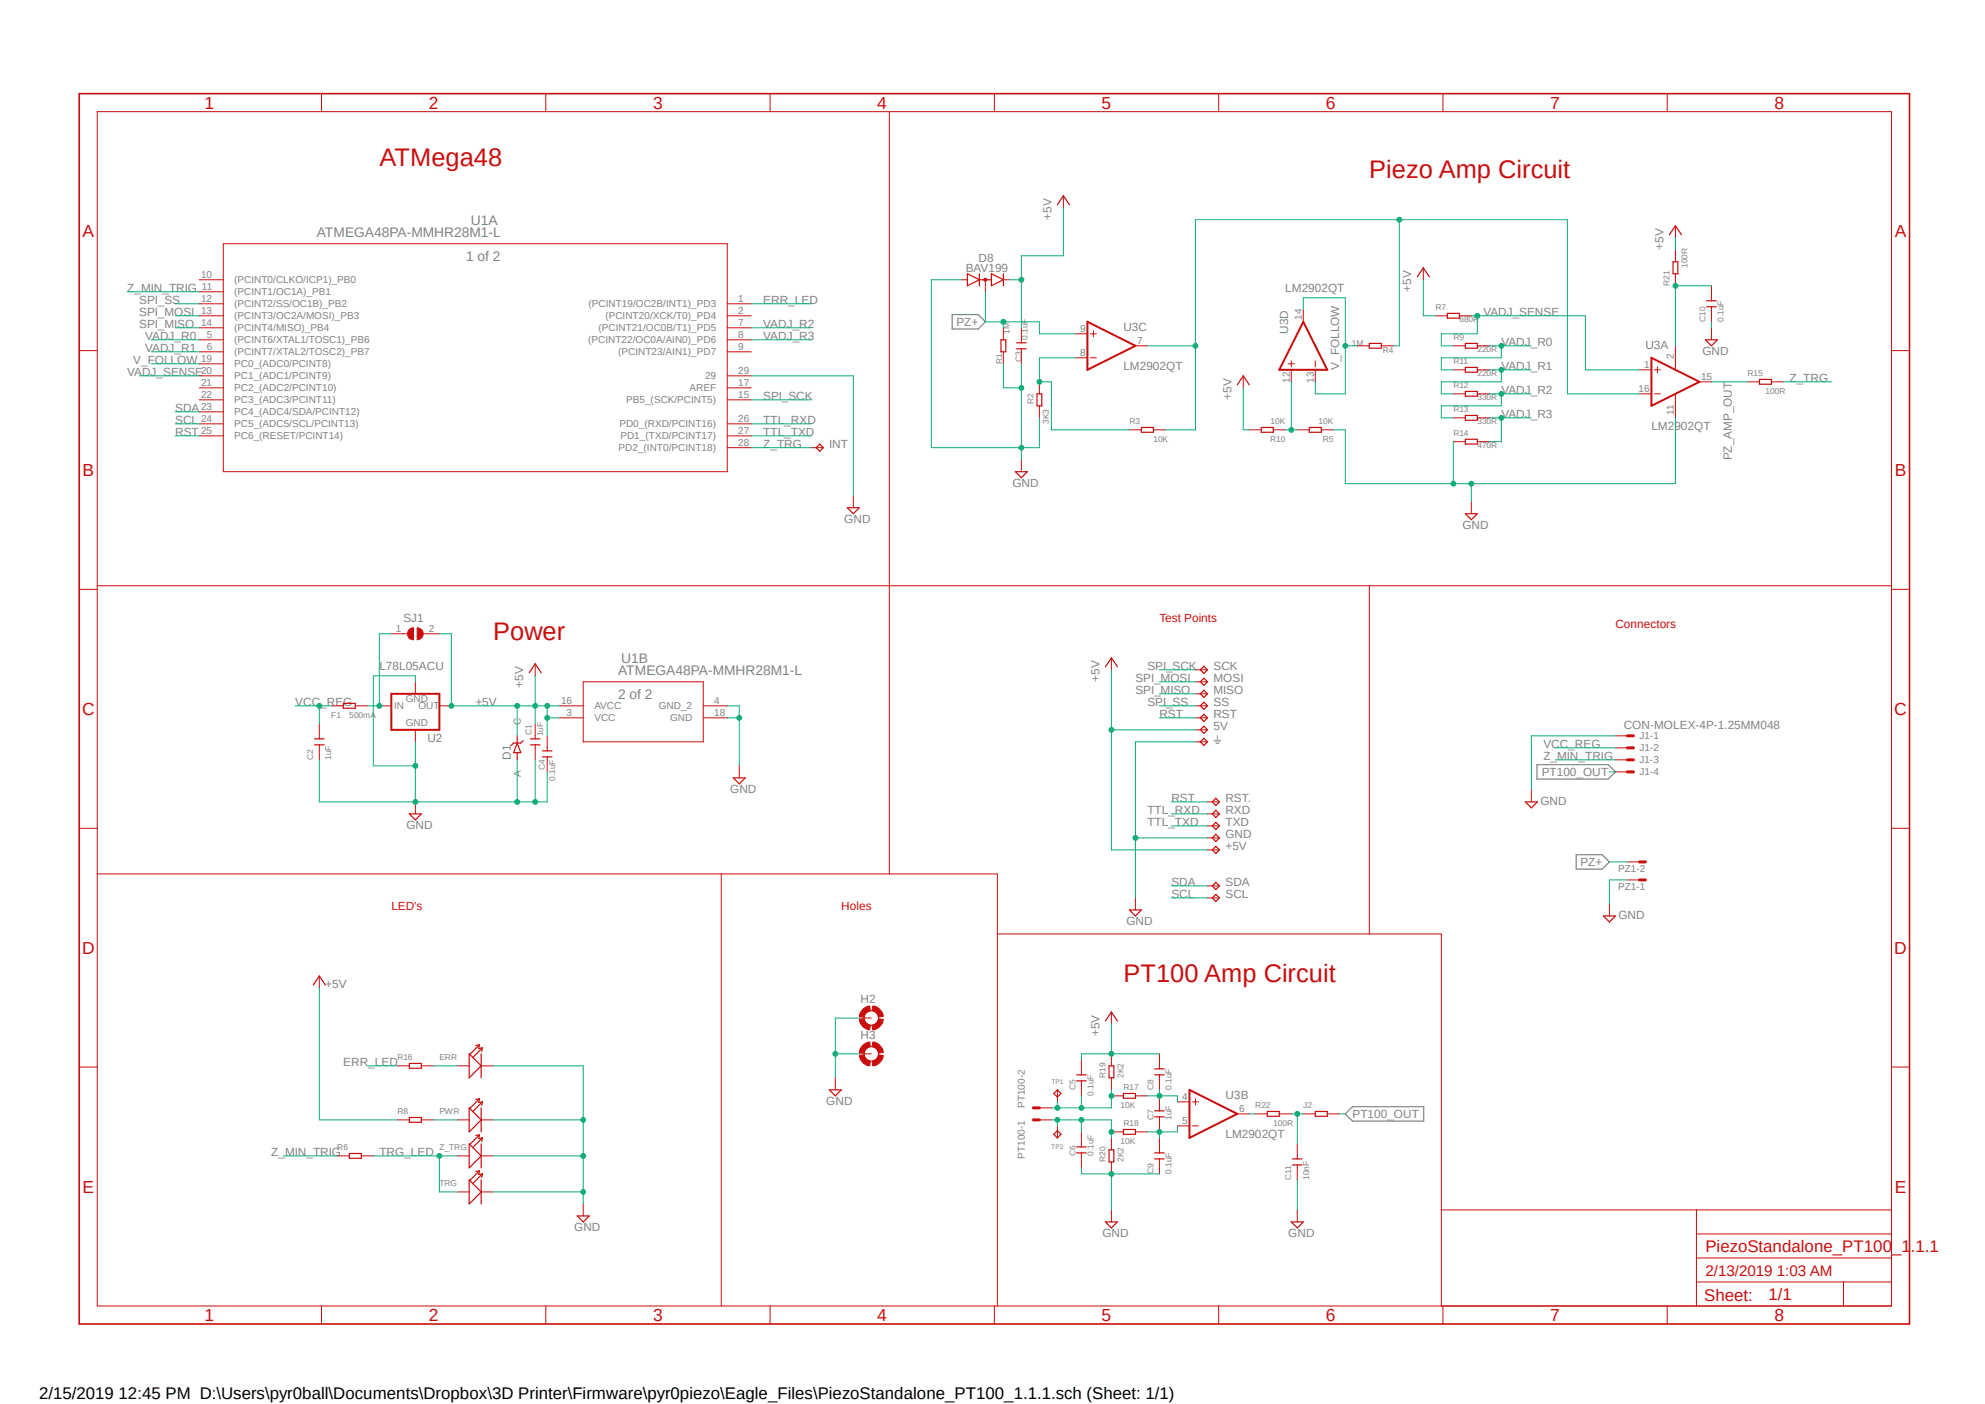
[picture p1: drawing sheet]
<svg xmlns="http://www.w3.org/2000/svg" width="420mm" height="297mm" viewBox="0 0 420 297" stroke-linecap="round" stroke-linejoin="round" font-family="sans-serif">
<defs><g id="words">
<g font-size="5.4" fill="#c90d0c">
<text x="80.3" y="35.1">ATMega48</text>
<text x="289.7" y="37.6">Piezo Amp Circuit</text>
<text x="104.3" y="135.3">Power</text>
<text x="237.7" y="207.7">PT100 Amp Circuit</text>
</g>
<g font-size="3.7" fill="#c90d0c">
<text x="43.3" y="23">1</text>
<text x="90.7" y="23">2</text>
<text x="138.2" y="23">3</text>
<text x="185.6" y="23">4</text>
<text x="233.1" y="23">5</text>
<text x="280.5" y="23">6</text>
<text x="328" y="23">7</text>
<text x="375.5" y="23">8</text>
<text x="17.4" y="50.2">A</text>
<text x="400.9" y="50.2">A</text>
<text x="17.4" y="100.7">B</text>
<text x="400.9" y="100.7">B</text>
<text x="17.4" y="151.3">C</text>
<text x="400.8" y="151.3">C</text>
<text x="17.4" y="201.8">D</text>
<text x="400.8" y="201.8">D</text>
<text x="17.4" y="252.3">E</text>
<text x="400.9" y="252.3">E</text>
<text x="43.3" y="279.5">1</text>
<text x="90.7" y="279.5">2</text>
<text x="138.2" y="279.5">3</text>
<text x="185.6" y="279.5">4</text>
<text x="233.1" y="279.5">5</text>
<text x="280.5" y="279.5">6</text>
<text x="328" y="279.5">7</text>
<text x="375.5" y="279.5">8</text>
</g>
<g font-size="3.6" fill="#c90d0c">
<text x="360.8" y="264.8">PiezoStandalone_PT100_1.1.1</text>
<text x="360.6" y="275.1">Sheet:</text>
<text x="374.2" y="275">1/1</text>
</g>
<text font-size="3.6" x="8.3" y="295.9">2/15/2019 12:45 PM D:\Users\pyr0ball\Documents\Dropbox\3D Printer\Firmware\pyr0piezo\Eagle_Files\PiezoStandalone_PT100_1.1.1.sch (Sheet: 1/1)</text>
<text font-size="3.2" fill="#c90d0c" x="360.8" y="269.9">2/13/2019 1:03 AM</text>
<g font-size="2.9" fill="#808080">
<text x="99.6" y="47.5">U1A</text>
<text x="67" y="50">ATMEGA48PA-MMHR28M1-L</text>
<text x="98.6" y="55.1">1 of 2</text>
<text x="130.8" y="142.7">ATMEGA48PA-MMHR28M1-L</text>
<text x="131.4" y="140.2">U1B</text>
<text x="130.8" y="147.8">2 of 2</text>
</g>
<g font-size="2.5" fill="#808080">
<text x="222.5" y="46.5" transform="rotate(-90 222.5 46.5)">+5V</text>
<text x="352" y="52.8" transform="rotate(-90 352 52.8)">+5V</text>
<text x="204.3" y="57.5">BAV199</text>
<text x="207.1" y="55.3">D8</text>
<text x="26.9" y="61.7">Z_MIN_TRIG</text>
<text x="29.5" y="64.3">SPI_SS</text>
<text x="161.5" y="64.3">ERR_LED</text>
<text x="271.9" y="61.7">LM2902QT</text>
<text x="298.6" y="61.7" transform="rotate(-90 298.6 61.7)">+5V</text>
<text x="29.5" y="69.3">SPI_MISO</text>
<text x="29.5" y="66.8">SPI_MOSI</text>
<text x="30.7" y="71.9">VADJ_R0</text>
<text x="161.5" y="69.3">VADJ_R2</text>
<text x="161.5" y="71.9">VADJ_R3</text>
<text x="202.4" y="69">PZ+</text>
<text x="237.7" y="70">U3C</text>
<text x="272.6" y="70.6" transform="rotate(-90 272.6 70.6)">U3D</text>
<text x="313.9" y="66.8">VADJ_SENSE</text>
<text x="28.2" y="77">V_FOLLOW</text>
<text x="30.7" y="74.4">VADJ_R1</text>
<text x="317.7" y="73.2">VADJ_R0</text>
<text x="348.1" y="73.8">U3A</text>
<text x="360.2" y="75.1">GND</text>
<text x="26.9" y="79.5">VADJ_SENSE</text>
<text x="237.7" y="78.2">LM2902QT</text>
<text x="283.4" y="78.2" transform="rotate(-90 283.4 78.2)">V_FOLLOW</text>
<text x="317.7" y="78.2">VADJ_R1</text>
<text x="317.7" y="83.3">VADJ_R2</text>
<text x="378.6" y="80.8">Z_TRG</text>
<text x="37.1" y="87.1">SDA</text>
<text x="37.1" y="89.7">SCL</text>
<text x="161.5" y="89.7">TTL_RXD</text>
<text x="161.5" y="84.6">SPI_SCK</text>
<text x="260.6" y="84.6" transform="rotate(-90 260.6 84.6)">+5V</text>
<text x="317.7" y="88.4">VADJ_R3</text>
<text x="37.1" y="92.2">RST</text>
<text x="161.5" y="92.2">TTL_TXD</text>
<text x="161.5" y="94.7">Z_TRG</text>
<text x="175.5" y="94.7">INT</text>
<text x="349.4" y="90.9">LM2902QT</text>
<text x="366.4" y="97.4" transform="rotate(-90 366.4 97.4)">PZ_AMP_OUT</text>
<text x="214.2" y="103">GND</text>
<text x="178.6" y="110.6">GND</text>
<text x="309.4" y="111.8">GND</text>
<text x="85.3" y="131.5">SJ1</text>
<text x="80.3" y="141.7">L78L05ACU</text>
<text x="242.8" y="141.7">SPI_SCK</text>
<text x="256.8" y="141.7">SCK</text>
<text x="62.5" y="149.3">VCC_REG</text>
<text x="100.6" y="149.3">+5V</text>
<text x="110.7" y="145.5" transform="rotate(-90 110.7 145.5)">+5V</text>
<text x="232.6" y="144.2" transform="rotate(-90 232.6 144.2)">+5V</text>
<text x="240.2" y="146.8">SPI_MISO</text>
<text x="240.2" y="144.2">SPI_MOSI</text>
<text x="242.8" y="149.3">SPI_SS</text>
<text x="256.8" y="144.2">MOSI</text>
<text x="256.8" y="146.8">MISO</text>
<text x="256.8" y="149.3">SS</text>
<text x="245.3" y="151.9">RST</text>
<text x="256.8" y="151.9">RST</text>
<text x="256.8" y="154.4">5V</text>
<text x="343.6" y="154.3">CON-MOLEX-4P-1.25MM048</text>
<text x="90.4" y="156.9">U2</text>
<text x="108.1" y="160.7" transform="rotate(-90 108.1 160.7)">D1</text>
<text x="256.8" y="157.4">⏚</text>
<text x="326.6" y="160.7">Z_MIN_TRIG</text>
<text x="326.6" y="158.2">VCC_REG</text>
<text x="154.5" y="167.7">GND</text>
<text x="326.2" y="164.2">PT100_OUT</text>
<text x="242.8" y="172.2">TTL_RXD</text>
<text x="247.9" y="169.6">RST</text>
<text x="259.3" y="172.2">RXD</text>
<text x="259.3" y="169.6">RST.</text>
<text x="325.9" y="170.3">GND</text>
<text x="86" y="175.3">GND</text>
<text x="242.8" y="174.7">TTL_TXD</text>
<text x="259.3" y="174.7">TXD</text>
<text x="259.3" y="177.2">GND</text>
<text x="259.3" y="179.8">+5V</text>
<text x="334.4" y="183.2">PZ+</text>
<text x="247.9" y="187.4">SDA</text>
<text x="247.9" y="190">SCL</text>
<text x="259.3" y="187.4">SDA</text>
<text x="259.3" y="190">SCL</text>
<text x="238.3" y="195.7">GND</text>
<text x="342.4" y="194.4">GND</text>
<text x="68.8" y="209">+5V</text>
<text x="182.1" y="212.2">H2</text>
<text x="182.1" y="219.8">H3</text>
<text x="232.6" y="219.2" transform="rotate(-90 232.6 219.2)">+5V</text>
<text x="72.6" y="225.5">ERR_LED</text>
<text x="174.8" y="233.7">GND</text>
<text x="259.3" y="232.5">U3B</text>
<text x="286.2" y="236.5">PT100_OUT</text>
<text x="57.4" y="244.5">Z_MIN_TRIG</text>
<text x="80.3" y="244.5">TRG_LED</text>
<text x="259.3" y="240.7">LM2902QT</text>
<text x="121.5" y="260.4">GND</text>
<text x="233.3" y="261.7">GND</text>
<text x="272.6" y="261.7">GND</text>
</g>
<g font-size="2.5" fill="#c90d0c">
<text x="245.3" y="131.5">Test Points</text>
<text x="341.8" y="132.8">Connectors</text>
<text x="82.8" y="192.5">LED's</text>
<text x="178" y="192.5">Holes</text>
</g>
<g font-size="2.1" fill="#808080">
<text x="42.5" y="58.8">10</text>
<text x="49.6" y="59.9">(PCINT0/CLKO/ICP1)_PB0</text>
<text x="42.5" y="63.9">12</text>
<text x="42.7" y="61.3">11</text>
<text x="49.6" y="62.5">(PCINT1/OC1A)_PB1</text>
<text x="49.6" y="65">(PCINT2/SS/OC1B)_PB2</text>
<text x="124.5" y="65">(PCINT19/OC2B/INT1)_PD3</text>
<text x="156.2" y="63.9">1</text>
<text x="42.5" y="66.4">13</text>
<text x="42.5" y="69">14</text>
<text x="43.7" y="71.5">5</text>
<text x="49.6" y="67.6">(PCINT3/OC2A/MOSI)_PB3</text>
<text x="49.6" y="70.1">(PCINT4/MISO)_PB4</text>
<text x="126.7" y="70.1">(PCINT21/OC0B/T1)_PD5</text>
<text x="128.1" y="67.6">(PCINT20/XCK/T0)_PD4</text>
<text x="156.2" y="66.4">2</text>
<text x="156.2" y="69">7</text>
<text x="156.2" y="71.5">8</text>
<text x="228.5" y="70.2">9</text>
<text x="275.4" y="67.7" transform="rotate(-90 275.4 67.7)">14</text>
<text x="42.5" y="76.6">19</text>
<text x="43.7" y="74">6</text>
<text x="49.6" y="72.6">(PCINT6/XTAL1/TOSC1)_PB6</text>
<text x="49.6" y="75.2">(PCINT7/XTAL2/TOSC2)_PB7</text>
<text x="49.6" y="77.7">PC0_(ADC0/PCINT8)</text>
<text x="124.5" y="72.6">(PCINT22/OC0A/AIN0)_PD6</text>
<text x="130.8" y="75.2">(PCINT23/AIN1)_PD7</text>
<text x="156.2" y="74">9</text>
<text x="228.5" y="75.3">8</text>
<text x="240.6" y="72.8">7</text>
<text x="347.9" y="77.9">1</text>
<text x="354.2" y="75.9" transform="rotate(-90 354.2 75.9)">2</text>
<text x="42.5" y="79.1">20</text>
<text x="42.5" y="81.7">21</text>
<text x="49.6" y="80.3">PC1_(ADC1/PCINT9)</text>
<text x="49.6" y="82.8">PC2_(ADC2/PCINT10)</text>
<text x="145.9" y="82.8">AREF</text>
<text x="149.2" y="80.3">29</text>
<text x="156.2" y="79.1">29</text>
<text x="156.2" y="81.7">17</text>
<text x="272.9" y="80.9" transform="rotate(-90 272.9 80.9)">12</text>
<text x="278" y="80.9" transform="rotate(-90 278 80.9)">13</text>
<text x="346.7" y="82.9">16</text>
<text x="359.9" y="80.4">15</text>
<text x="42.5" y="84.2">22</text>
<text x="42.5" y="86.7">23</text>
<text x="42.5" y="89.3">24</text>
<text x="49.6" y="85.3">PC3_(ADC3/PCINT11)</text>
<text x="49.6" y="87.9">PC4_(ADC4/SDA/PCINT12)</text>
<text x="132.5" y="85.3">PB5_(SCK/PCINT5)</text>
<text x="156.2" y="84.2">15</text>
<text x="156.2" y="89.3">26</text>
<text x="354.2" y="87.8" transform="rotate(-90 354.2 87.8)">11</text>
<text x="42.5" y="91.8">25</text>
<text x="49.6" y="90.4">PC5_(ADC5/SCL/PCINT13)</text>
<text x="49.6" y="93">PC6_(RESET/PCINT14)</text>
<text x="130.9" y="95.5">PD2_(INT0/PCINT18)</text>
<text x="131.1" y="90.4">PD0_(RXD/PCINT16)</text>
<text x="131.3" y="93">PD1_(TXD/PCINT17)</text>
<text x="156.2" y="91.8">27</text>
<text x="156.2" y="94.4">28</text>
<text x="83.8" y="133.7">1</text>
<text x="90.8" y="133.7">2</text>
<text x="83.4" y="149.9">IN</text>
<text x="85.9" y="148.5">GND</text>
<text x="88.5" y="149.9">OUT</text>
<text x="118.7" y="149">16</text>
<text x="151.1" y="149">4</text>
<text x="85.9" y="153.6">GND</text>
<text x="110.2" y="153.3" transform="rotate(-90 110.2 153.3)">C</text>
<text x="119.9" y="151.5">3</text>
<text x="125.8" y="150.1">AVCC</text>
<text x="125.8" y="152.6">VCC</text>
<text x="139.4" y="150.1">GND_2</text>
<text x="141.8" y="152.6">GND</text>
<text x="151.1" y="151.5">18</text>
<text x="346.9" y="156.4">J1-1</text>
<text x="346.9" y="159">J1-2</text>
<text x="346.9" y="161.5">J1-3</text>
<text x="110.2" y="164.5" transform="rotate(-90 110.2 164.5)">A</text>
<text x="346.9" y="164">J1-4</text>
<text x="342.3" y="184.4">PZ1-2</text>
<text x="342.3" y="188.2">PZ1-1</text>
<text x="250.1" y="232.7">4</text>
<text x="216.9" y="234.4" transform="rotate(-90 216.9 234.4)">PT100-2</text>
<text x="250.1" y="237.8">5</text>
<text x="262.2" y="235.3">6</text>
<text x="216.9" y="245.1" transform="rotate(-90 216.9 245.1)">PT100-1</text>
</g>
<g font-size="1.8" fill="#808080">
<text x="357" y="56.6" transform="rotate(-90 357 56.6)">100R</text>
<text x="303.7" y="65.5">R7</text>
<text x="353.2" y="60.5" transform="rotate(-90 353.2 60.5)">R21</text>
<text x="213.6" y="70.6" transform="rotate(-90 213.6 70.6)">1M</text>
<text x="217.4" y="71.9" transform="rotate(-90 217.4 71.9)">0.1uF</text>
<text x="307.5" y="71.9">R9</text>
<text x="308.8" y="68.1">680R</text>
<text x="360.8" y="68.1" transform="rotate(-90 360.8 68.1)">C10</text>
<text x="364.7" y="68.1" transform="rotate(-90 364.7 68.1)">0.1uF</text>
<text x="212" y="77" transform="rotate(-90 212 77)">R1</text>
<text x="216.1" y="76.7" transform="rotate(-90 216.1 76.7)">C3</text>
<text x="286" y="73.2">1M</text>
<text x="292.6" y="74.7">R4</text>
<text x="307.5" y="77">R11</text>
<text x="312.6" y="74.4">220R</text>
<text x="307.5" y="82">R12</text>
<text x="312.6" y="79.5">220R</text>
<text x="369.7" y="79.5">R15</text>
<text x="373.5" y="83.3">100R</text>
<text x="218.7" y="85.6" transform="rotate(-90 218.7 85.6)">R2</text>
<text x="222" y="89.7" transform="rotate(-90 222 89.7)">3K3</text>
<text x="239" y="89.7">R3</text>
<text x="268.8" y="89.7">10K</text>
<text x="279" y="89.7">10K</text>
<text x="307.5" y="87.1">R13</text>
<text x="312.6" y="84.6">330R</text>
<text x="312.6" y="89.7">330R</text>
<text x="244.1" y="93.5">10K</text>
<text x="268.7" y="93.5">R10</text>
<text x="279.9" y="93.5">R5</text>
<text x="307.5" y="92.2">R14</text>
<text x="312.6" y="94.7">470R</text>
<text x="70.1" y="151.8">F1</text>
<text x="73.9" y="151.8">500mA</text>
<text x="112.5" y="155.5" transform="rotate(-90 112.5 155.5)">C1</text>
<text x="114.9" y="155.8" transform="rotate(-90 114.9 155.8)">1uF</text>
<text x="66.3" y="160.7" transform="rotate(-90 66.3 160.7)">C2</text>
<text x="70.1" y="160.7" transform="rotate(-90 70.1 160.7)">1uF</text>
<text x="115.3" y="162.9" transform="rotate(-90 115.3 162.9)">C4</text>
<text x="117.4" y="165.2" transform="rotate(-90 117.4 165.2)">0.1uF</text>
<text x="84.1" y="224.2">R16</text>
<text x="93" y="224.2">ERR</text>
<text x="227.5" y="230.5" transform="rotate(-90 227.5 230.5)">C5</text>
<text x="231.4" y="231.8" transform="rotate(-90 231.4 231.8)">0.1uF</text>
<text x="233.9" y="228" transform="rotate(-90 233.9 228)">R19</text>
<text x="237.7" y="228" transform="rotate(-90 237.7 228)">2K2</text>
<text x="237.7" y="230.5">R17</text>
<text x="244.1" y="230.5" transform="rotate(-90 244.1 230.5)">C8</text>
<text x="247.9" y="230.5" transform="rotate(-90 247.9 230.5)">0.1uF</text>
<text x="84.1" y="235.6">R8</text>
<text x="93" y="235.6">PWR</text>
<text x="237.1" y="234.4">10K</text>
<text x="237.7" y="238.2">R18</text>
<text x="244.1" y="236.9" transform="rotate(-90 244.1 236.9)">C7</text>
<text x="247.9" y="236.9" transform="rotate(-90 247.9 236.9)">1uF</text>
<text x="265.6" y="234.4">R22</text>
<text x="269.4" y="238.2">100R</text>
<text x="275.8" y="234.4">J2</text>
<text x="71.4" y="243.2">R6</text>
<text x="93" y="243.2">Z_TRG</text>
<text x="227.5" y="244.5" transform="rotate(-90 227.5 244.5)">C6</text>
<text x="231.4" y="244.5" transform="rotate(-90 231.4 244.5)">0.1uF</text>
<text x="233.9" y="245.8" transform="rotate(-90 233.9 245.8)">R20</text>
<text x="237.1" y="242">10K</text>
<text x="237.7" y="245.8" transform="rotate(-90 237.7 245.8)">2K2</text>
<text x="93" y="250.9">TRG</text>
<text x="244.1" y="248.3" transform="rotate(-90 244.1 248.3)">C9</text>
<text x="247.9" y="248.3" transform="rotate(-90 247.9 248.3)">0.1uF</text>
<text x="273.2" y="249.6" transform="rotate(-90 273.2 249.6)">C11</text>
<text x="277" y="249.6" transform="rotate(-90 277 249.6)">10nF</text>
</g>
<g font-size="1.4" fill="#808080">
<text x="222.5" y="229.3">TP1</text>
<text x="222.4" y="243">TP2</text>
</g>
</g></defs>
<path d="M16.3 19.5l395.7 261.1M412 19.5l-395.7 261.1" fill="none" stroke="#fff" stroke-width=".21"/>
<path d="M201.5 66.5h5.5l1.5 1.6-1.5 1.5h-5.5zM325.2 161.8h15.1l1.5 1.5-1.5 1.5h-15.1zM333.5 180.8h5.5l1.5 1.5-1.5 1.6h-5.5zM284.6 235.6l1.6-1.5h15v3.1h-15z" fill="none" stroke="#808080" stroke-width=".25"/>
<g fill="none" stroke="#c90d0c" stroke-width=".21">
<path d="M188.2 23.6v161.3M42.2 59.2h5M47.2 51.6h106.7v48.2h-106.7zM42.2 64.3h5M42.2 66.8h5M42.2 69.3h5M42.2 71.9h5M42.2 74.4h5M42.2 79.5h5M42.2 61.7h5M42.2 77h5M153.9 64.3h5.1"/>
<path d="M153.9 66.8h5.1M153.9 69.3h5.1M153.9 71.9h5.1M153.9 74.4h5.1M153.9 79.5h5.1M42.2 82h5M42.2 84.6h5M42.2 89.7h5M42.2 92.2h5M42.2 87.1h5M153.9 82h5.1M153.9 84.6h5.1"/>
<path d="M153.9 89.7h5.1M153.9 92.2h5.1M153.9 94.7h5.1M20.6 123.9h379.6M289.7 123.9v73.7M80.3 149.3h2.5M87.9 144.2v2.6M87.9 154.4v2.5M93 149.3h2.5M118.3 149.3h5.1M118.3 151.8h5.1M123.4 144.2h25.4v12.7h-25.4z"/>
<path d="M148.8 149.3h5.1M148.8 151.8h5.1M87.9 169.6v2.6M156.4 162v2.5M20.6 184.9h190.4v91.4M152.6 184.9v91.4M211 197.6h94v58.3M344.3 186.1h2.6M344.3 182.3h2.6M96.8 244.5h2.5M101.8 244.5h2.6"/>
<circle cx="184.4" cy="215.3" r="1.53"/>
</g>
<path d="M346.9 186.1h1.2M346.9 182.3h1.2" fill="none" stroke="#c90d0c" stroke-width=".63"/>
<path d="M82.8 146.8h10.2v7.6h-10.2z" fill="none" stroke="#c90d0c" stroke-width=".42"/>
<path d="M86.6 172.2h2.6l-1.3 1.2zM155.2 164.5h2.5l-1.3 1.3zM99.3 242l2.5 2.5-2.5 2.6zM101.4 240.1l-2 2M101.4 240.1l-.7 .1M101.4 240.1l-.1 .7 .8-.1M101.8 242v5.1M102.1 240.7l-2.1 2M102.1 240.7l-.2 .8" fill="none" stroke="#c90d0c" stroke-width=".25"/>
<path d="M184.7 212.8a2.44 2.44 0 0 1 2.2 2.2l-1 .1a1.56 1.56 0 0 0-1.4-1.3z" fill-rule="evenodd" fill="#c90d0c"/>
<path d="M184.7 212.8a2.44 2.44 0 0 1 2.2 2.2l-1 .1a1.56 1.56 0 0 0-1.4-1.3z" fill="none" stroke="#c90d0c" stroke-width=".21"/>
<path d="M182.8 213.3l1.2-.5 .1 1a1.57 1.57 0 0 0-1.3 1.3l-1-.1a2.35 2.35 0 0 1 1-1.7z" fill-rule="evenodd" fill="#c90d0c"/>
<path d="M182.8 213.3l1.2-.5 .1 1a1.57 1.57 0 0 0-1.3 1.3l-1-.1a2.35 2.35 0 0 1 1-1.7z" fill="none" stroke="#c90d0c" stroke-width=".21"/>
<path d="M181.8 215.6l1-.1a1.57 1.57 0 0 0 1.3 1.4l-.1 .9a2.45 2.45 0 0 1-2.2-2.2z" fill-rule="evenodd" fill="#c90d0c"/>
<path d="M181.8 215.6l1-.1a1.57 1.57 0 0 0 1.3 1.4l-.1 .9a2.45 2.45 0 0 1-2.2-2.2z" fill="none" stroke="#c90d0c" stroke-width=".21"/>
<path d="M185.9 215.5l1 .1a2.57 2.57 0 0 1-2.2 2.2l-.2-.9a1.56 1.56 0 0 0 1.4-1.4z" fill-rule="evenodd" fill="#c90d0c"/>
<g fill="none" stroke="#c90d0c" stroke-width=".21">
<path d="M181.8 215.3h2.6M184.5 216.9a1.56 1.56 0 0 0 1.4-1.4l1 .1a2.57 2.57 0 0 1-2.2 2.2z"/>
<circle cx="184.4" cy="222.9" r="1.53"/>
</g>
<path d="M184.7 220.4a2.44 2.44 0 0 1 2.2 2.2l-1 .2a1.56 1.56 0 0 0-1.4-1.4z" fill-rule="evenodd" fill="#c90d0c"/>
<path d="M184.7 220.4a2.44 2.44 0 0 1 2.2 2.2l-1 .2a1.56 1.56 0 0 0-1.4-1.4z" fill="none" stroke="#c90d0c" stroke-width=".21"/>
<path d="M182.8 220.9l1.2-.5 .1 1a1.57 1.57 0 0 0-1.3 1.4l-1-.2a2.35 2.35 0 0 1 1-1.7z" fill-rule="evenodd" fill="#c90d0c"/>
<path d="M182.8 220.9l1.2-.5 .1 1a1.57 1.57 0 0 0-1.3 1.4l-1-.2a2.35 2.35 0 0 1 1-1.7z" fill="none" stroke="#c90d0c" stroke-width=".21"/>
<path d="M181.8 223.3l1-.2a1.57 1.57 0 0 0 1.3 1.4l-.1 1a2.45 2.45 0 0 1-2.2-2.2z" fill-rule="evenodd" fill="#c90d0c"/>
<path d="M181.8 223.3l1-.2a1.57 1.57 0 0 0 1.3 1.4l-.1 1a2.45 2.45 0 0 1-2.2-2.2z" fill="none" stroke="#c90d0c" stroke-width=".21"/>
<path d="M185.9 223.1l1 .2a2.57 2.57 0 0 1-2.2 2.2l-.2-1a1.56 1.56 0 0 0 1.4-1.4z" fill-rule="evenodd" fill="#c90d0c"/>
<g fill="none" stroke="#c90d0c" stroke-width=".21">
<path d="M68 19.8v3.8M115.5 19.8v3.8M162.9 19.8v3.8M210.4 19.8v3.8M257.9 19.8v3.8M305.3 19.8v3.8M352.8 19.8v3.8M20.6 23.6h379.6v252.7h-379.6zM203.4 59.2h1.3M212.3 59.2h1.3M16.8 74.2h3.8M212.3 69.3v2.6"/>
<path d="M212.3 74.4v2.6M400.2 74.2h3.8M171.7 94.7h2.5M219.9 80.8v2.5M219.9 85.9v2.5M264.3 90.9h2.6M269.4 90.9h2.5M274.5 90.9h2.5M279.6 90.9h2.5M180.6 104.9v2.5M311.3 106.1v2.6M16.8 124.7h3.8"/>
<path d="M400.2 124.7h3.8M67.6 153.1v3.2M67.6 157.6v3.1M113.2 153.1v3.2M113.2 157.6v3.1M252.9 141.7h2.6M252.9 144.2h2.6M252.9 146.8h2.6M252.9 149.3h2.6M252.9 151.8h2.6M252.9 154.4h2.6M16.8 175.2h3.8"/>
<path d="M255.5 172.2h2.5M255.5 174.7h2.5M255.5 177.2h2.5M255.5 179.8h2.5M255.5 169.6h2.5M400.2 175.2h3.8M240.2 189.9v2.6M255.5 187.4h2.5M255.5 189.9h2.5M16.8 225.7h3.8M84.1 236.9h2.5M89.2 236.9h2.5"/>
<path d="M96.8 236.9h2.5M101.8 236.9h2.6M176.7 228v2.5M181.8 222.9h2.6M184.5 224.5a1.56 1.56 0 0 0 1.4-1.4l1 .2a2.57 2.57 0 0 1-2.2 2.2zM400.2 225.7h3.8M71.4 244.5h2.5M76.5 244.5h2.5M96.8 252.1h2.5M101.8 252.1h2.6M123.4 254.7v2.5M358.9 255.9v20.4"/>
<path d="M400.2 255.9h-95.2v20.4M68 276.3v3.8M115.5 276.3v3.8M162.9 276.3v3.8M210.4 276.3v3.8M257.9 276.3v3.8M305.3 276.3v3.8M352.8 276.3v3.8M358.9 271.2h41.3M358.9 266.1h41.3M358.9 261h41.3M390.1 271.2v5.1"/>
</g>
<g fill="none" stroke="#c90d0c" stroke-width=".25">
<path d="M204.7 57.9l2.5 1.3-2.5 1.3zM207.2 57.9v2.6M207.2 59.2h2.6M209.8 57.9l2.5 1.3-2.5 1.3zM212.3 57.9v2.6M211.8 71.9h1v2.5h-1zM173.4 93.9l.8 .8-.8 .8-.7-.8zM219.4 83.3h1v2.6h-1zM266.9 90.4h2.5v1h-2.5zM277 90.4h2.6v1h-2.6zM179.3 107.4h2.5l-1.2 1.3zM310 108.7h2.6l-1.3 1.2z"/>
<path d="M66.5 157.6h2.1M66.5 156.3h2.1M112.2 157.6h2.1M112.2 156.3h2.1M254.7 140.9l.8 .8-.8 .8-.7-.8zM254.7 143.5l.8 .7-.8 .8-.7-.8zM254.7 146l.8 .8-.8 .7-.7-.7zM254.7 148.5l.8 .8-.8 .8-.7-.8zM254.7 151.1l.8 .7-.8 .8-.7-.8zM254.7 153.6l.8 .8-.8 .8-.7-.8zM257.3 171.4l.7 .8-.7 .7-.8-.7zM257.3 173.9l.7 .8-.7 .8-.8-.8z"/>
<path d="M257.3 176.5l.7 .7-.7 .8-.8-.8zM257.3 179l.7 .8-.7 .8-.8-.8zM257.3 168.9l.7 .7-.7 .8-.8-.8zM239 192.5h2.5l-1.3 1.3zM257.3 186.6l.7 .8-.7 .8-.8-.8zM257.3 189.2l.7 .7-.7 .8-.8-.8zM86.6 236.4h2.6v1h-2.6zM99.3 234.4l2.5 2.5-2.5 2.5zM101.4 232.5l-2 2M101.4 232.5l-.7 .1M101.4 232.5l-.1 .7 .8-.1M101.8 234.4v5"/>
<path d="M102.1 233.1l-2.1 2M102.1 233.1l-.2 .7M175.5 230.5h2.5l-1.3 1.3zM73.9 244h2.6v1h-2.6zM99.3 249.6l2.5 2.5-2.5 2.6zM101.4 247.7l-2 2M101.4 247.7l-.7 .1M101.4 247.7l-.1 .8 .8-.2M101.8 249.6v5.1M102.1 248.3l-2.1 2.1M102.1 248.3l-.2 .8M122.1 257.2h2.6l-1.3 1.3z"/>
</g>
<path d="M16.8 19.8h387.2v260.3h-387.2z" fill="none" stroke="#c90d0c" stroke-width=".34"/>
<path d="M208.2 58.9h.5l.1 .3-.1 .2-.2 .1-.3-.1z" fill-rule="evenodd" fill="#c90d0c"/>
<g fill="none" stroke="#c90d0c" stroke-width=".21">
<path d="M208.2 58.9h.5l.1 .3-.1 .2-.2 .1-.3-.1zM208.5 59.2v2.5M225 41.4v2.5M301.2 56.6v2.6M354.5 47.8v2.5M216.1 69.3v3.2M216.1 73.8v3.2M263.1 79.5v2.5M287.2 73.2h2.5M292.3 73.2h2.5M303.7 66.8h2.5M307.5 73.2h2.5"/>
<path d="M307.5 78.2h2.5M308.8 66.8h2.5M312.6 73.2h2.5M312.6 78.2h2.5M216.1 97.2v2.6M239 90.9h2.5M244.1 90.9h2.5M307.5 83.3h2.5M307.5 88.4h2.5M307.5 93.4h2.5M312.6 83.3h2.5M312.6 88.4h2.5"/>
<path d="M312.6 93.4h2.5M369.7 80.8h2.6M374.8 80.8h2.6M235.2 139.1v2.6M70.1 149.3h2.5M75.2 149.3h2.5M113.2 140.4v2.6M252.9 156.9h2.6M341.8 155.7h2.5M341.8 158.2h2.5M324 167.1v2.5M341.8 160.7h2.5"/>
<path d="M67.6 206.5v2.5M84.1 225.5h2.5M89.2 225.5h2.5M96.8 225.5h2.5M101.8 225.5h2.6"/>
</g>
<g fill="none" stroke="#c90d0c" stroke-width=".25">
<path d="M223.7 43.3l1.3-1.9 1.3 1.9M299.9 58.5l1.3-1.9 1.2 1.9M353.2 49.7l1.3-1.9 1.3 1.9M215.1 73.8h2M215.1 72.5h2M289.7 72.6h2.6v1.1h-2.6zM306.2 66.3h2.6v1h-2.6zM310 72.6h2.6v1.1h-2.6zM310 77.7h2.6v1h-2.6zM214.8 99.8h2.6l-1.3 1.2zM241.5 90.4h2.6v1h-2.6zM261.8 81.4l1.3-1.9 1.2 1.9"/>
<path d="M310 82.8h2.6v1h-2.6zM310 87.9h2.6v1h-2.6zM310 92.9h2.6v1h-2.6zM372.3 80.3h2.5v1h-2.5zM72.6 148.8h2.6v1h-2.6zM109.4 157.2l.8 2h-1.5zM109.4 155.7v1.4M109.4 159.3v1.4M110.7 156.7l-.5 .5h-1.5l-.5 .5M112 142.3l1.2-1.9 1.3 1.9M233.9 141.1l1.3-2 1.2 2M254.7 156.2l.8 .7-.8 .8-.7-.8z"/>
<path d="M322.7 169.6h2.6l-1.3 1.3zM66.3 208.4l1.3-1.9 1.2 1.9M86.6 225h2.6v1h-2.6zM99.3 222.9l2.5 2.6-2.5 2.5zM101.4 221l-2 2.1M101.4 221l-.7 .1M101.4 221l-.1 .8 .8-.1M101.8 222.9v5.1M102.1 221.7l-2.1 2M102.1 221.7l-.2 .7"/>
</g>
<path d="M344.3 155.7h1.3M344.3 158.2h1.3M344.3 160.7h1.3" fill="none" stroke="#c90d0c" stroke-width=".63"/>
<path d="M88.3 132.8a1.27 1.27 0 0 1 1.3 1.3 1.27 1.27 0 0 1-1.3 1.2z" fill-rule="evenodd" fill="#c90d0c"/>
<path d="M88.3 132.8a1.27 1.27 0 0 1 1.3 1.3 1.27 1.27 0 0 1-1.3 1.2z" fill="none" stroke="#c90d0c" stroke-width=".21"/>
<path d="M86.6 133.2l.3-.3 .6-.1v2.5a1.27 1.27 0 0 1-1.2-.7 1.27 1.27 0 0 1 .3-1.4z" fill-rule="evenodd" fill="#c90d0c"/>
<g fill="none" stroke="#c90d0c" stroke-width=".21">
<path d="M354.5 52.8v2.6M354.5 57.9v2.6M227.5 70.6h2.6M227.5 75.7h2.6M230.7 70.6h1.3M230.7 75.7h1.3M231.4 70v1.2M240.2 73.2h2.6M272.6 77h1.3M273.2 76.3v1.3M273.2 78.2v2.6M275.8 65.5v2.6"/>
<path d="M278.3 76.3v1.3M278.3 78.2v2.6M346.9 78.2h2.5M350.1 78.2h1.2M350.7 77.6v1.3M354.5 73.2v5M362.1 60.5v3.1M362.1 64.9v3.2M362.1 69.3v2.6M346.9 83.3h2.5M350.1 83.3h1.2M354.5 83.3v5.1"/>
<path d="M359.6 80.8h2.5M82.8 134.1h3.4M86.6 133.2l.3-.3 .6-.1v2.5a1.27 1.27 0 0 1-1.2-.7 1.27 1.27 0 0 1 .3-1.4zM89.5 134.1h3.5M115.8 155.7v3.1M115.8 160.1v3.2M341.8 163.3h2.5M340.5 191.2v2.6M235.2 214.1v2.5M219.9 236.9h2.6M219.9 234.4h2.6M223.7 230.5v2.6"/>
<path d="M223.7 238.2v2.5M228.8 224.2v3.2M228.8 228.6v3.2M228.8 239.4v3.2M235.2 231.8h2.5M235.2 239.4h2.5M235.2 222.9v2.6M235.2 228v2.5M240.2 231.8h2.6M240.2 239.4h2.6M245.3 222.9v3.2M245.3 227.4v3.1"/>
<path d="M245.3 231.8v3.2M245.3 236.3v3.1M249.1 233.1h2.6M249.1 238.2h2.6M252.3 233.1h1.3M252.3 238.2h1.3M252.9 232.5v1.2M261.8 235.6h2.5M265.6 235.6h2.5M270.7 235.6h2.5M275.8 235.6h2.5M280.8 235.6h2.6"/>
<path d="M228.8 243.9v3.2M235.2 240.7v2.5M235.2 245.8v2.5M235.2 255.9v2.6M245.3 240.7v3.2M245.3 245.2v3.1M274.5 242v3.2M274.5 246.4v3.2M274.5 255.9v2.6"/>
</g>
<g fill="none" stroke="#c90d0c" stroke-width=".25">
<path d="M354 55.4h1v2.5h-1zM360.8 71.9h2.6l-1.3 1.3zM361.1 64.9h2M361.1 63.6h2M114.8 158.8h2M114.8 160.1h2M339.3 193.8h2.5l-1.3 1.2zM233.9 216l1.3-1.9 1.2 1.9M223 231.3l.7-.8 .8 .8-.8 .8zM223 239.9l.7-.7 .8 .7-.8 .8zM227.8 228.6h2M227.8 227.4h2"/>
<path d="M234.7 225.5h1v2.5h-1zM237.7 231.3h2.5v1h-2.5zM237.7 238.9h2.5v1h-2.5zM244.3 227.4h2M244.3 236.3h2M244.3 235h2M244.3 226.1h2M268.1 235.1h2.6v1h-2.6zM278.3 235.1h2.5v1h-2.5zM227.8 243.9h2M227.8 242.6h2M233.9 258.5h2.5l-1.2 1.3z"/>
<path d="M234.7 243.2h1v2.6h-1zM244.3 243.9h2M244.3 245.2h2M273.2 258.5h2.6l-1.3 1.3zM273.5 245.2h2M273.5 246.4h2"/>
</g>
<path d="M230.1 68.1l10.1 5.1-10.1 5zM275.8 68.1l5 10.1h-10.1zM349.4 75.7l10.2 5.1-10.2 5.1zM251.7 230.5l10.1 5.1-10.1 5.1z" fill="none" stroke="#c90d0c" stroke-width=".42"/>
<path d="M344.3 163.3h1.3M218.7 236.9h1.2M218.7 234.4h1.2" fill="none" stroke="#c90d0c" stroke-width=".63"/>
<path d="M153.9 151.8h2.5M153.9 149.3h2.5v12.7" fill="none" stroke="#0dab76" stroke-width=".21"/>
<circle cx="156.4" cy="151.8" r=".51" fill="#0dab76"/>
<g fill="none" stroke="#0dab76" stroke-width=".21">
<path d="M113.2 160.7v8.9h-3.8"/>
<circle cx="156.4" cy="151.8" r=".51"/>
</g>
<circle cx="87.9" cy="169.6" r=".51" fill="#0dab76"/>
<g fill="none" stroke="#0dab76" stroke-width=".21">
<path d="M87.9 144.2v-1.2h-8.9v19h8.9M87.9 156.9v12.7M67.6 160.7v8.9h41.8"/>
<circle cx="87.9" cy="169.6" r=".51"/>
</g>
<circle cx="87.9" cy="162" r=".51" fill="#0dab76"/>
<g fill="none" stroke="#0dab76" stroke-width=".21">
<path d="M109.4 160.7v8.9"/>
<circle cx="87.9" cy="162" r=".51"/>
</g>
<circle cx="109.4" cy="169.6" r=".51" fill="#0dab76"/>
<g fill="none" stroke="#0dab76" stroke-width=".21">
<path d="M115.8 163.3v6.3h-2.6"/>
<circle cx="109.4" cy="169.6" r=".51"/>
</g>
<circle cx="113.2" cy="169.6" r=".51" fill="#0dab76"/>
<g fill="none" stroke="#0dab76" stroke-width=".21">
<path d="M181.8 215.3h-5.1v7.6h5.1"/>
<circle cx="113.2" cy="169.6" r=".51"/>
</g>
<circle cx="176.7" cy="222.9" r=".51" fill="#0dab76"/>
<g fill="none" stroke="#0dab76" stroke-width=".21">
<path d="M176.7 222.9v5.1M104.4 244.5h19v10.2M104.4 252.1h19"/>
<circle cx="176.7" cy="222.9" r=".51"/>
</g>
<circle cx="123.4" cy="252.1" r=".51" fill="#0dab76"/>
<g fill="none" stroke="#0dab76" stroke-width=".21">
<path d="M104.4 236.9h19v7.6"/>
<circle cx="123.4" cy="252.1" r=".51"/>
</g>
<circle cx="123.4" cy="244.5" r=".51" fill="#0dab76"/>
<g fill="none" stroke="#0dab76" stroke-width=".21">
<path d="M104.4 225.5h19v11.4"/>
<circle cx="123.4" cy="244.5" r=".51"/>
</g>
<circle cx="123.4" cy="236.9" r=".51" fill="#0dab76"/>
<g fill="none" stroke="#0dab76" stroke-width=".21">
<path d="M252.9 156.9h-12.7v33M240.2 177.2h15.3"/>
<circle cx="123.4" cy="236.9" r=".51"/>
</g>
<circle cx="240.2" cy="177.2" r=".51" fill="#0dab76"/>
<g fill="none" stroke="#0dab76" stroke-width=".21">
<path d="M159 79.5h21.6v25.4M282.1 90.9h2.5v11.4h22.9M354.5 102.3h-43.2v3.8"/>
<circle cx="240.2" cy="177.2" r=".51"/>
</g>
<circle cx="311.3" cy="102.3" r=".51" fill="#0dab76"/>
<g fill="none" stroke="#0dab76" stroke-width=".21">
<path d="M307.5 93.4v8.9h3.8"/>
<circle cx="311.3" cy="102.3" r=".51"/>
</g>
<circle cx="307.5" cy="102.3" r=".51" fill="#0dab76"/>
<g fill="none" stroke="#0dab76" stroke-width=".21">
<path d="M203.4 59.2h-6.3v35.5h19v2.5M354.5 88.4v13.9"/>
<circle cx="307.5" cy="102.3" r=".51"/>
</g>
<circle cx="216.1" cy="94.7" r=".51" fill="#0dab76"/>
<g fill="none" stroke="#0dab76" stroke-width=".21">
<path d="M212.3 77v5h3.8M216.1 77v17.7h3.8"/>
<circle cx="216.1" cy="94.7" r=".51"/>
</g>
<circle cx="216.1" cy="82" r=".51" fill="#0dab76"/>
<g fill="none" stroke="#0dab76" stroke-width=".21">
<path d="M362.1 68.1v1.2M219.9 88.4v6.3M341.8 155.7h-17.8v11.4M245.3 248.3h-10.1v7.6"/>
<circle cx="216.1" cy="82" r=".51"/>
</g>
<circle cx="235.2" cy="248.3" r=".51" fill="#0dab76"/>
<g fill="none" stroke="#0dab76" stroke-width=".21">
<path d="M26.9 61.7h15.3M62.5 149.3h7.6M67.6 149.3v3.8M329.1 160.7h12.7M344.3 186.1h-3.8v5.1M59.9 244.5h11.5M228.8 247.1v1.2h6.4M274.5 249.6v6.3"/>
<circle cx="235.2" cy="248.3" r=".51"/>
</g>
<circle cx="67.6" cy="149.3" r=".51" fill="#0dab76"/>
<g fill="none" stroke="#0dab76" stroke-width=".21">
<path d="M37.1 69.3h5.1M37.1 66.8h5.1M37.1 64.3h5.1M37.1 89.7h5.1M37.1 92.2h5.1M37.1 87.1h5.1M159 89.7h12.7M159 92.2h12.7M159 84.6h12.7M245.3 151.8h7.6M245.3 141.7h7.6M245.3 146.8h7.6"/>
<path d="M245.3 144.2h7.6M245.3 149.3h7.6M329.1 158.2h12.7M247.9 172.2h7.6M247.9 174.7h7.6M247.9 169.6h7.6M247.9 187.4h7.6M247.9 189.9h7.6M79 244.5h17.8M93 244.5v7.6h3.8"/>
<circle cx="67.6" cy="149.3" r=".51"/>
</g>
<circle cx="93" cy="244.5" r=".51" fill="#0dab76"/>
<g fill="none" stroke="#0dab76" stroke-width=".21">
<path d="M208.5 61.7v6.4h11.4M212.3 68.1v1.2M159 94.7h12.7M377.4 80.8h10.1M91.7 236.9h5.1"/>
<circle cx="93" cy="244.5" r=".51"/>
</g>
<circle cx="212.3" cy="68.1" r=".51" fill="#0dab76"/>
<g fill="none" stroke="#0dab76" stroke-width=".21">
<path d="M219.9 68.1v2.5h7.6M235.2 141.7v38.1h20.3M235.2 154.4h17.7M340.5 182.3h3.8"/>
<circle cx="212.3" cy="68.1" r=".51"/>
</g>
<circle cx="235.2" cy="154.4" r=".51" fill="#0dab76"/>
<g fill="none" stroke="#0dab76" stroke-width=".21">
<path d="M95.5 149.3h22.8M115.8 149.3v2.5h2.5"/>
<circle cx="235.2" cy="154.4" r=".51"/>
</g>
<circle cx="115.8" cy="149.3" r=".51" fill="#0dab76"/>
<g fill="none" stroke="#0dab76" stroke-width=".21">
<path d="M113.2 149.3v3.8"/>
<circle cx="115.8" cy="149.3" r=".51"/>
</g>
<circle cx="113.2" cy="149.3" r=".51" fill="#0dab76"/>
<g fill="none" stroke="#0dab76" stroke-width=".21">
<path d="M109.4 149.3v6.4M113.2 143v6.3"/>
<circle cx="113.2" cy="149.3" r=".51"/>
</g>
<circle cx="109.4" cy="149.3" r=".51" fill="#0dab76"/>
<g fill="none" stroke="#0dab76" stroke-width=".21">
<path d="M93 134.1h2.5v15.2"/>
<circle cx="109.4" cy="149.3" r=".51"/>
</g>
<circle cx="95.5" cy="149.3" r=".51" fill="#0dab76"/>
<g fill="none" stroke="#0dab76" stroke-width=".21">
<path d="M115.8 151.8v3.9"/>
<circle cx="95.5" cy="149.3" r=".51"/>
</g>
<circle cx="115.8" cy="151.8" r=".51" fill="#0dab76"/>
<g fill="none" stroke="#0dab76" stroke-width=".21">
<path d="M213.6 59.2h2.5M225 43.9v10.2h-8.9v15.2M67.6 209v27.9h16.5"/>
<circle cx="115.8" cy="151.8" r=".51"/>
</g>
<circle cx="216.1" cy="59.2" r=".51" fill="#0dab76"/>
<g fill="none" stroke="#0dab76" stroke-width=".21">
<path d="M301.2 59.2v7.6h2.5M354.5 50.3v2.5M263.1 82v8.9h1.2M235.2 216.6v6.3h-6.4v1.3"/>
<circle cx="216.1" cy="59.2" r=".51"/>
</g>
<circle cx="235.2" cy="222.9" r=".51" fill="#0dab76"/>
<g fill="none" stroke="#0dab76" stroke-width=".21">
<path d="M219.9 80.8h2.6M235.2 222.9h10.1"/>
<circle cx="235.2" cy="222.9" r=".51"/>
</g>
<circle cx="219.9" cy="80.8" r=".51" fill="#0dab76"/>
<g fill="none" stroke="#0dab76" stroke-width=".21">
<path d="M296.1 46.5v26.7h-1.3M227.5 75.7h-7.6v5.1M222.5 80.8v10.1h16.5M331.6 83.3v-36.8h-78.7v44.4h-6.3"/>
<circle cx="219.9" cy="80.8" r=".51"/>
</g>
<circle cx="296.1" cy="46.5" r=".51" fill="#0dab76"/>
<g fill="none" stroke="#0dab76" stroke-width=".21">
<path d="M242.8 73.2h10.1M331.6 83.3h15.3"/>
<circle cx="296.1" cy="46.5" r=".51"/>
</g>
<circle cx="252.9" cy="73.2" r=".51" fill="#0dab76"/>
<g fill="none" stroke="#0dab76" stroke-width=".21">
<path d="M271.9 90.9h2.6M273.2 80.8v10.1"/>
<circle cx="252.9" cy="73.2" r=".51"/>
</g>
<circle cx="273.2" cy="90.9" r=".51" fill="#0dab76"/>
<g fill="none" stroke="#0dab76" stroke-width=".21">
<path d="M275.8 63h8.8v20.3h-6.3M284.6 73.2h2.6"/>
<circle cx="273.2" cy="90.9" r=".51"/>
</g>
<circle cx="284.6" cy="73.2" r=".51" fill="#0dab76"/>
<g fill="none" stroke="#0dab76" stroke-width=".21">
<path d="M32 77h10.2M275.8 63v2.5M311.3 66.8h24.1v11.4M312.6 66.8v3.8h-7.6v2.6h2.5M278.3 80.8v2.5"/>
<circle cx="284.6" cy="73.2" r=".51"/>
</g>
<circle cx="312.6" cy="66.8" r=".51" fill="#0dab76"/>
<g fill="none" stroke="#0dab76" stroke-width=".21">
<path d="M29.5 79.5h12.7M315.1 73.2h8.9M317.7 73.2v2.5h-12.7v2.5h2.5M335.4 78.2h11.5"/>
<circle cx="312.6" cy="66.8" r=".51"/>
</g>
<circle cx="317.7" cy="73.2" r=".51" fill="#0dab76"/>
<g fill="none" stroke="#0dab76" stroke-width=".21">
<path d="M32 71.9h10.2M315.1 78.2h8.9M317.7 78.2v2.6h-12.7v2.5h2.5"/>
<circle cx="317.7" cy="73.2" r=".51"/>
</g>
<circle cx="317.7" cy="78.2" r=".51" fill="#0dab76"/>
<g fill="none" stroke="#0dab76" stroke-width=".21">
<path d="M32 74.4h10.2M315.1 83.3h8.9M317.7 83.3v2.6h-12.7v2.5h2.5"/>
<circle cx="317.7" cy="78.2" r=".51"/>
</g>
<circle cx="317.7" cy="83.3" r=".51" fill="#0dab76"/>
<g fill="none" stroke="#0dab76" stroke-width=".21">
<path d="M159 69.3h12.7M315.1 88.4h8.9M317.7 88.4v5h-2.6"/>
<circle cx="317.7" cy="83.3" r=".51"/>
</g>
<circle cx="317.7" cy="88.4" r=".51" fill="#0dab76"/>
<g fill="none" stroke="#0dab76" stroke-width=".21">
<path d="M159 71.9h12.7M159 64.3h12.7M362.1 80.8h7.6M82.8 134.1h-2.5v15.2h-2.6M77.7 225.5h6.4M91.7 225.5h5.1"/>
<circle cx="317.7" cy="88.4" r=".51"/>
</g>
<circle cx="80.3" cy="149.3" r=".51" fill="#0dab76"/>
<g fill="none" stroke="#0dab76" stroke-width=".21">
<path d="M362.1 60.5h-7.6v12.7"/>
<circle cx="80.3" cy="149.3" r=".51"/>
</g>
<circle cx="354.5" cy="60.5" r=".51" fill="#0dab76"/>
<g fill="none" stroke="#0dab76" stroke-width=".21">
<path d="M223.7 233.1v1.3M235.2 231.8v2.6h-12.7"/>
<circle cx="354.5" cy="60.5" r=".51"/>
</g>
<circle cx="223.7" cy="234.4" r=".51" fill="#0dab76"/>
<g fill="none" stroke="#0dab76" stroke-width=".21">
<path d="M228.8 231.8v2.6"/>
<circle cx="223.7" cy="234.4" r=".51"/>
</g>
<circle cx="228.8" cy="234.4" r=".51" fill="#0dab76"/>
<g fill="none" stroke="#0dab76" stroke-width=".21">
<path d="M235.2 230.5v1.3"/>
<circle cx="228.8" cy="234.4" r=".51"/>
</g>
<circle cx="235.2" cy="231.8" r=".51" fill="#0dab76"/>
<g fill="none" stroke="#0dab76" stroke-width=".21">
<path d="M222.5 236.9h12.7v2.5M223.7 236.9v1.3"/>
<circle cx="235.2" cy="231.8" r=".51"/>
</g>
<circle cx="223.7" cy="236.9" r=".51" fill="#0dab76"/>
<g fill="none" stroke="#0dab76" stroke-width=".21">
<path d="M228.8 236.9v2.5"/>
<circle cx="223.7" cy="236.9" r=".51"/>
</g>
<circle cx="228.8" cy="236.9" r=".51" fill="#0dab76"/>
<g fill="none" stroke="#0dab76" stroke-width=".21">
<path d="M235.2 239.4v1.3"/>
<circle cx="228.8" cy="236.9" r=".51"/>
</g>
<circle cx="235.2" cy="239.4" r=".51" fill="#0dab76"/>
<g fill="none" stroke="#0dab76" stroke-width=".21">
<path d="M249.1 238.2v1.2h-6.3"/>
<circle cx="235.2" cy="239.4" r=".51"/>
</g>
<circle cx="245.3" cy="239.4" r=".51" fill="#0dab76"/>
<g fill="none" stroke="#0dab76" stroke-width=".21">
<path d="M242.8 231.8h6.3v1.3M245.3 239.4v1.3"/>
<circle cx="245.3" cy="239.4" r=".51"/>
</g>
<circle cx="245.3" cy="231.8" r=".51" fill="#0dab76"/>
<g fill="none" stroke="#0dab76" stroke-width=".21">
<path d="M245.3 230.5v1.3M264.3 235.6h1.3M273.2 235.6h2.6M274.5 235.6v6.4"/>
<circle cx="245.3" cy="231.8" r=".51"/>
</g>
<circle cx="274.5" cy="235.6" r=".51" fill="#0dab76"/>
<g fill="none" stroke="#0dab76" stroke-width=".21">
<path d="M340.5 163.3h1.3M283.4 235.6h1.2"/>
<circle cx="274.5" cy="235.6" r=".51"/>
</g>
<use href="#words"/>
</svg>
